VERSION 5.7 ;
BUSBITCHARS "[]" ;
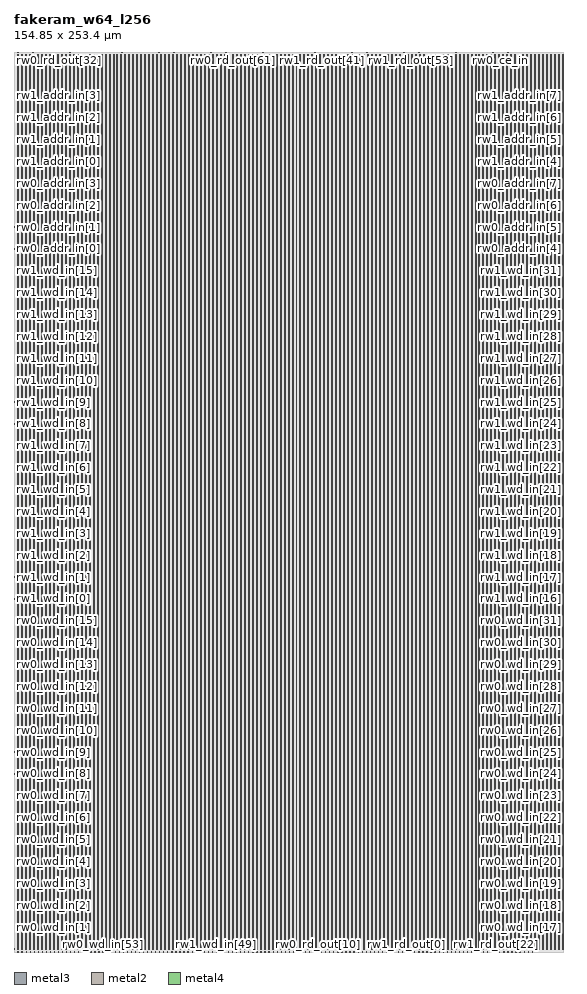
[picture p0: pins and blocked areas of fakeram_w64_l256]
MACRO fakeram_w64_l256
  FOREIGN fakeram_w64_l256 0 0 ;
  SYMMETRY X Y R90 ;
  SIZE 154.850 BY 253.400 ;
  CLASS BLOCK ;
  PIN rw0_wd_in[0]
    DIRECTION INPUT ;
    USE SIGNAL ;
    SHAPE ABUTMENT ;
    PORT
      LAYER metal3 ;
      RECT 0.000 0.805 0.210 0.875 ;
    END
  END rw0_wd_in[0]
  PIN rw0_wd_in[1]
    DIRECTION INPUT ;
    USE SIGNAL ;
    SHAPE ABUTMENT ;
    PORT
      LAYER metal3 ;
      RECT 0.000 6.965 0.210 7.035 ;
    END
  END rw0_wd_in[1]
  PIN rw0_wd_in[2]
    DIRECTION INPUT ;
    USE SIGNAL ;
    SHAPE ABUTMENT ;
    PORT
      LAYER metal3 ;
      RECT 0.000 13.125 0.210 13.195 ;
    END
  END rw0_wd_in[2]
  PIN rw0_wd_in[3]
    DIRECTION INPUT ;
    USE SIGNAL ;
    SHAPE ABUTMENT ;
    PORT
      LAYER metal3 ;
      RECT 0.000 19.285 0.210 19.355 ;
    END
  END rw0_wd_in[3]
  PIN rw0_wd_in[4]
    DIRECTION INPUT ;
    USE SIGNAL ;
    SHAPE ABUTMENT ;
    PORT
      LAYER metal3 ;
      RECT 0.000 25.445 0.210 25.515 ;
    END
  END rw0_wd_in[4]
  PIN rw0_wd_in[5]
    DIRECTION INPUT ;
    USE SIGNAL ;
    SHAPE ABUTMENT ;
    PORT
      LAYER metal3 ;
      RECT 0.000 31.605 0.210 31.675 ;
    END
  END rw0_wd_in[5]
  PIN rw0_wd_in[6]
    DIRECTION INPUT ;
    USE SIGNAL ;
    SHAPE ABUTMENT ;
    PORT
      LAYER metal3 ;
      RECT 0.000 37.765 0.210 37.835 ;
    END
  END rw0_wd_in[6]
  PIN rw0_wd_in[7]
    DIRECTION INPUT ;
    USE SIGNAL ;
    SHAPE ABUTMENT ;
    PORT
      LAYER metal3 ;
      RECT 0.000 43.925 0.210 43.995 ;
    END
  END rw0_wd_in[7]
  PIN rw0_wd_in[8]
    DIRECTION INPUT ;
    USE SIGNAL ;
    SHAPE ABUTMENT ;
    PORT
      LAYER metal3 ;
      RECT 0.000 50.085 0.210 50.155 ;
    END
  END rw0_wd_in[8]
  PIN rw0_wd_in[9]
    DIRECTION INPUT ;
    USE SIGNAL ;
    SHAPE ABUTMENT ;
    PORT
      LAYER metal3 ;
      RECT 0.000 56.245 0.210 56.315 ;
    END
  END rw0_wd_in[9]
  PIN rw0_wd_in[10]
    DIRECTION INPUT ;
    USE SIGNAL ;
    SHAPE ABUTMENT ;
    PORT
      LAYER metal3 ;
      RECT 0.000 62.405 0.210 62.475 ;
    END
  END rw0_wd_in[10]
  PIN rw0_wd_in[11]
    DIRECTION INPUT ;
    USE SIGNAL ;
    SHAPE ABUTMENT ;
    PORT
      LAYER metal3 ;
      RECT 0.000 68.565 0.210 68.635 ;
    END
  END rw0_wd_in[11]
  PIN rw0_wd_in[12]
    DIRECTION INPUT ;
    USE SIGNAL ;
    SHAPE ABUTMENT ;
    PORT
      LAYER metal3 ;
      RECT 0.000 74.725 0.210 74.795 ;
    END
  END rw0_wd_in[12]
  PIN rw0_wd_in[13]
    DIRECTION INPUT ;
    USE SIGNAL ;
    SHAPE ABUTMENT ;
    PORT
      LAYER metal3 ;
      RECT 0.000 80.885 0.210 80.955 ;
    END
  END rw0_wd_in[13]
  PIN rw0_wd_in[14]
    DIRECTION INPUT ;
    USE SIGNAL ;
    SHAPE ABUTMENT ;
    PORT
      LAYER metal3 ;
      RECT 0.000 87.045 0.210 87.115 ;
    END
  END rw0_wd_in[14]
  PIN rw0_wd_in[15]
    DIRECTION INPUT ;
    USE SIGNAL ;
    SHAPE ABUTMENT ;
    PORT
      LAYER metal3 ;
      RECT 0.000 93.205 0.210 93.275 ;
    END
  END rw0_wd_in[15]
  PIN rw0_wd_in[16]
    DIRECTION INPUT ;
    USE SIGNAL ;
    SHAPE ABUTMENT ;
    PORT
      LAYER metal3 ;
      RECT 154.640 0.805 154.850 0.875 ;
    END
  END rw0_wd_in[16]
  PIN rw0_wd_in[17]
    DIRECTION INPUT ;
    USE SIGNAL ;
    SHAPE ABUTMENT ;
    PORT
      LAYER metal3 ;
      RECT 154.640 6.965 154.850 7.035 ;
    END
  END rw0_wd_in[17]
  PIN rw0_wd_in[18]
    DIRECTION INPUT ;
    USE SIGNAL ;
    SHAPE ABUTMENT ;
    PORT
      LAYER metal3 ;
      RECT 154.640 13.125 154.850 13.195 ;
    END
  END rw0_wd_in[18]
  PIN rw0_wd_in[19]
    DIRECTION INPUT ;
    USE SIGNAL ;
    SHAPE ABUTMENT ;
    PORT
      LAYER metal3 ;
      RECT 154.640 19.285 154.850 19.355 ;
    END
  END rw0_wd_in[19]
  PIN rw0_wd_in[20]
    DIRECTION INPUT ;
    USE SIGNAL ;
    SHAPE ABUTMENT ;
    PORT
      LAYER metal3 ;
      RECT 154.640 25.445 154.850 25.515 ;
    END
  END rw0_wd_in[20]
  PIN rw0_wd_in[21]
    DIRECTION INPUT ;
    USE SIGNAL ;
    SHAPE ABUTMENT ;
    PORT
      LAYER metal3 ;
      RECT 154.640 31.605 154.850 31.675 ;
    END
  END rw0_wd_in[21]
  PIN rw0_wd_in[22]
    DIRECTION INPUT ;
    USE SIGNAL ;
    SHAPE ABUTMENT ;
    PORT
      LAYER metal3 ;
      RECT 154.640 37.765 154.850 37.835 ;
    END
  END rw0_wd_in[22]
  PIN rw0_wd_in[23]
    DIRECTION INPUT ;
    USE SIGNAL ;
    SHAPE ABUTMENT ;
    PORT
      LAYER metal3 ;
      RECT 154.640 43.925 154.850 43.995 ;
    END
  END rw0_wd_in[23]
  PIN rw0_wd_in[24]
    DIRECTION INPUT ;
    USE SIGNAL ;
    SHAPE ABUTMENT ;
    PORT
      LAYER metal3 ;
      RECT 154.640 50.085 154.850 50.155 ;
    END
  END rw0_wd_in[24]
  PIN rw0_wd_in[25]
    DIRECTION INPUT ;
    USE SIGNAL ;
    SHAPE ABUTMENT ;
    PORT
      LAYER metal3 ;
      RECT 154.640 56.245 154.850 56.315 ;
    END
  END rw0_wd_in[25]
  PIN rw0_wd_in[26]
    DIRECTION INPUT ;
    USE SIGNAL ;
    SHAPE ABUTMENT ;
    PORT
      LAYER metal3 ;
      RECT 154.640 62.405 154.850 62.475 ;
    END
  END rw0_wd_in[26]
  PIN rw0_wd_in[27]
    DIRECTION INPUT ;
    USE SIGNAL ;
    SHAPE ABUTMENT ;
    PORT
      LAYER metal3 ;
      RECT 154.640 68.565 154.850 68.635 ;
    END
  END rw0_wd_in[27]
  PIN rw0_wd_in[28]
    DIRECTION INPUT ;
    USE SIGNAL ;
    SHAPE ABUTMENT ;
    PORT
      LAYER metal3 ;
      RECT 154.640 74.725 154.850 74.795 ;
    END
  END rw0_wd_in[28]
  PIN rw0_wd_in[29]
    DIRECTION INPUT ;
    USE SIGNAL ;
    SHAPE ABUTMENT ;
    PORT
      LAYER metal3 ;
      RECT 154.640 80.885 154.850 80.955 ;
    END
  END rw0_wd_in[29]
  PIN rw0_wd_in[30]
    DIRECTION INPUT ;
    USE SIGNAL ;
    SHAPE ABUTMENT ;
    PORT
      LAYER metal3 ;
      RECT 154.640 87.045 154.850 87.115 ;
    END
  END rw0_wd_in[30]
  PIN rw0_wd_in[31]
    DIRECTION INPUT ;
    USE SIGNAL ;
    SHAPE ABUTMENT ;
    PORT
      LAYER metal3 ;
      RECT 154.640 93.205 154.850 93.275 ;
    END
  END rw0_wd_in[31]
  PIN rw0_wd_in[32]
    DIRECTION INPUT ;
    USE SIGNAL ;
    SHAPE ABUTMENT ;
    PORT
      LAYER metal2 ;
      RECT 1.105 0.000 1.175 0.210 ;
    END
  END rw0_wd_in[32]
  PIN rw0_wd_in[33]
    DIRECTION INPUT ;
    USE SIGNAL ;
    SHAPE ABUTMENT ;
    PORT
      LAYER metal2 ;
      RECT 2.245 0.000 2.315 0.210 ;
    END
  END rw0_wd_in[33]
  PIN rw0_wd_in[34]
    DIRECTION INPUT ;
    USE SIGNAL ;
    SHAPE ABUTMENT ;
    PORT
      LAYER metal2 ;
      RECT 3.385 0.000 3.455 0.210 ;
    END
  END rw0_wd_in[34]
  PIN rw0_wd_in[35]
    DIRECTION INPUT ;
    USE SIGNAL ;
    SHAPE ABUTMENT ;
    PORT
      LAYER metal2 ;
      RECT 4.525 0.000 4.595 0.210 ;
    END
  END rw0_wd_in[35]
  PIN rw0_wd_in[36]
    DIRECTION INPUT ;
    USE SIGNAL ;
    SHAPE ABUTMENT ;
    PORT
      LAYER metal2 ;
      RECT 5.665 0.000 5.735 0.210 ;
    END
  END rw0_wd_in[36]
  PIN rw0_wd_in[37]
    DIRECTION INPUT ;
    USE SIGNAL ;
    SHAPE ABUTMENT ;
    PORT
      LAYER metal2 ;
      RECT 6.805 0.000 6.875 0.210 ;
    END
  END rw0_wd_in[37]
  PIN rw0_wd_in[38]
    DIRECTION INPUT ;
    USE SIGNAL ;
    SHAPE ABUTMENT ;
    PORT
      LAYER metal2 ;
      RECT 7.945 0.000 8.015 0.210 ;
    END
  END rw0_wd_in[38]
  PIN rw0_wd_in[39]
    DIRECTION INPUT ;
    USE SIGNAL ;
    SHAPE ABUTMENT ;
    PORT
      LAYER metal2 ;
      RECT 9.085 0.000 9.155 0.210 ;
    END
  END rw0_wd_in[39]
  PIN rw0_wd_in[40]
    DIRECTION INPUT ;
    USE SIGNAL ;
    SHAPE ABUTMENT ;
    PORT
      LAYER metal2 ;
      RECT 10.225 0.000 10.295 0.210 ;
    END
  END rw0_wd_in[40]
  PIN rw0_wd_in[41]
    DIRECTION INPUT ;
    USE SIGNAL ;
    SHAPE ABUTMENT ;
    PORT
      LAYER metal2 ;
      RECT 11.365 0.000 11.435 0.210 ;
    END
  END rw0_wd_in[41]
  PIN rw0_wd_in[42]
    DIRECTION INPUT ;
    USE SIGNAL ;
    SHAPE ABUTMENT ;
    PORT
      LAYER metal2 ;
      RECT 12.505 0.000 12.575 0.210 ;
    END
  END rw0_wd_in[42]
  PIN rw0_wd_in[43]
    DIRECTION INPUT ;
    USE SIGNAL ;
    SHAPE ABUTMENT ;
    PORT
      LAYER metal2 ;
      RECT 13.645 0.000 13.715 0.210 ;
    END
  END rw0_wd_in[43]
  PIN rw0_wd_in[44]
    DIRECTION INPUT ;
    USE SIGNAL ;
    SHAPE ABUTMENT ;
    PORT
      LAYER metal2 ;
      RECT 14.785 0.000 14.855 0.210 ;
    END
  END rw0_wd_in[44]
  PIN rw0_wd_in[45]
    DIRECTION INPUT ;
    USE SIGNAL ;
    SHAPE ABUTMENT ;
    PORT
      LAYER metal2 ;
      RECT 15.925 0.000 15.995 0.210 ;
    END
  END rw0_wd_in[45]
  PIN rw0_wd_in[46]
    DIRECTION INPUT ;
    USE SIGNAL ;
    SHAPE ABUTMENT ;
    PORT
      LAYER metal2 ;
      RECT 17.065 0.000 17.135 0.210 ;
    END
  END rw0_wd_in[46]
  PIN rw0_wd_in[47]
    DIRECTION INPUT ;
    USE SIGNAL ;
    SHAPE ABUTMENT ;
    PORT
      LAYER metal2 ;
      RECT 18.205 0.000 18.275 0.210 ;
    END
  END rw0_wd_in[47]
  PIN rw0_wd_in[48]
    DIRECTION INPUT ;
    USE SIGNAL ;
    SHAPE ABUTMENT ;
    PORT
      LAYER metal2 ;
      RECT 19.345 0.000 19.415 0.210 ;
    END
  END rw0_wd_in[48]
  PIN rw0_wd_in[49]
    DIRECTION INPUT ;
    USE SIGNAL ;
    SHAPE ABUTMENT ;
    PORT
      LAYER metal2 ;
      RECT 20.485 0.000 20.555 0.210 ;
    END
  END rw0_wd_in[49]
  PIN rw0_wd_in[50]
    DIRECTION INPUT ;
    USE SIGNAL ;
    SHAPE ABUTMENT ;
    PORT
      LAYER metal2 ;
      RECT 21.625 0.000 21.695 0.210 ;
    END
  END rw0_wd_in[50]
  PIN rw0_wd_in[51]
    DIRECTION INPUT ;
    USE SIGNAL ;
    SHAPE ABUTMENT ;
    PORT
      LAYER metal2 ;
      RECT 22.765 0.000 22.835 0.210 ;
    END
  END rw0_wd_in[51]
  PIN rw0_wd_in[52]
    DIRECTION INPUT ;
    USE SIGNAL ;
    SHAPE ABUTMENT ;
    PORT
      LAYER metal2 ;
      RECT 23.905 0.000 23.975 0.210 ;
    END
  END rw0_wd_in[52]
  PIN rw0_wd_in[53]
    DIRECTION INPUT ;
    USE SIGNAL ;
    SHAPE ABUTMENT ;
    PORT
      LAYER metal2 ;
      RECT 25.045 0.000 25.115 0.210 ;
    END
  END rw0_wd_in[53]
  PIN rw0_wd_in[54]
    DIRECTION INPUT ;
    USE SIGNAL ;
    SHAPE ABUTMENT ;
    PORT
      LAYER metal2 ;
      RECT 26.185 0.000 26.255 0.210 ;
    END
  END rw0_wd_in[54]
  PIN rw0_wd_in[55]
    DIRECTION INPUT ;
    USE SIGNAL ;
    SHAPE ABUTMENT ;
    PORT
      LAYER metal2 ;
      RECT 27.325 0.000 27.395 0.210 ;
    END
  END rw0_wd_in[55]
  PIN rw0_wd_in[56]
    DIRECTION INPUT ;
    USE SIGNAL ;
    SHAPE ABUTMENT ;
    PORT
      LAYER metal2 ;
      RECT 28.465 0.000 28.535 0.210 ;
    END
  END rw0_wd_in[56]
  PIN rw0_wd_in[57]
    DIRECTION INPUT ;
    USE SIGNAL ;
    SHAPE ABUTMENT ;
    PORT
      LAYER metal2 ;
      RECT 29.605 0.000 29.675 0.210 ;
    END
  END rw0_wd_in[57]
  PIN rw0_wd_in[58]
    DIRECTION INPUT ;
    USE SIGNAL ;
    SHAPE ABUTMENT ;
    PORT
      LAYER metal2 ;
      RECT 30.745 0.000 30.815 0.210 ;
    END
  END rw0_wd_in[58]
  PIN rw0_wd_in[59]
    DIRECTION INPUT ;
    USE SIGNAL ;
    SHAPE ABUTMENT ;
    PORT
      LAYER metal2 ;
      RECT 31.885 0.000 31.955 0.210 ;
    END
  END rw0_wd_in[59]
  PIN rw0_wd_in[60]
    DIRECTION INPUT ;
    USE SIGNAL ;
    SHAPE ABUTMENT ;
    PORT
      LAYER metal2 ;
      RECT 33.025 0.000 33.095 0.210 ;
    END
  END rw0_wd_in[60]
  PIN rw0_wd_in[61]
    DIRECTION INPUT ;
    USE SIGNAL ;
    SHAPE ABUTMENT ;
    PORT
      LAYER metal2 ;
      RECT 34.165 0.000 34.235 0.210 ;
    END
  END rw0_wd_in[61]
  PIN rw0_wd_in[62]
    DIRECTION INPUT ;
    USE SIGNAL ;
    SHAPE ABUTMENT ;
    PORT
      LAYER metal2 ;
      RECT 35.305 0.000 35.375 0.210 ;
    END
  END rw0_wd_in[62]
  PIN rw0_wd_in[63]
    DIRECTION INPUT ;
    USE SIGNAL ;
    SHAPE ABUTMENT ;
    PORT
      LAYER metal2 ;
      RECT 36.445 0.000 36.515 0.210 ;
    END
  END rw0_wd_in[63]
  PIN rw1_wd_in[0]
    DIRECTION INPUT ;
    USE SIGNAL ;
    SHAPE ABUTMENT ;
    PORT
      LAYER metal3 ;
      RECT 0.000 99.365 0.210 99.435 ;
    END
  END rw1_wd_in[0]
  PIN rw1_wd_in[1]
    DIRECTION INPUT ;
    USE SIGNAL ;
    SHAPE ABUTMENT ;
    PORT
      LAYER metal3 ;
      RECT 0.000 105.525 0.210 105.595 ;
    END
  END rw1_wd_in[1]
  PIN rw1_wd_in[2]
    DIRECTION INPUT ;
    USE SIGNAL ;
    SHAPE ABUTMENT ;
    PORT
      LAYER metal3 ;
      RECT 0.000 111.685 0.210 111.755 ;
    END
  END rw1_wd_in[2]
  PIN rw1_wd_in[3]
    DIRECTION INPUT ;
    USE SIGNAL ;
    SHAPE ABUTMENT ;
    PORT
      LAYER metal3 ;
      RECT 0.000 117.845 0.210 117.915 ;
    END
  END rw1_wd_in[3]
  PIN rw1_wd_in[4]
    DIRECTION INPUT ;
    USE SIGNAL ;
    SHAPE ABUTMENT ;
    PORT
      LAYER metal3 ;
      RECT 0.000 124.005 0.210 124.075 ;
    END
  END rw1_wd_in[4]
  PIN rw1_wd_in[5]
    DIRECTION INPUT ;
    USE SIGNAL ;
    SHAPE ABUTMENT ;
    PORT
      LAYER metal3 ;
      RECT 0.000 130.165 0.210 130.235 ;
    END
  END rw1_wd_in[5]
  PIN rw1_wd_in[6]
    DIRECTION INPUT ;
    USE SIGNAL ;
    SHAPE ABUTMENT ;
    PORT
      LAYER metal3 ;
      RECT 0.000 136.325 0.210 136.395 ;
    END
  END rw1_wd_in[6]
  PIN rw1_wd_in[7]
    DIRECTION INPUT ;
    USE SIGNAL ;
    SHAPE ABUTMENT ;
    PORT
      LAYER metal3 ;
      RECT 0.000 142.485 0.210 142.555 ;
    END
  END rw1_wd_in[7]
  PIN rw1_wd_in[8]
    DIRECTION INPUT ;
    USE SIGNAL ;
    SHAPE ABUTMENT ;
    PORT
      LAYER metal3 ;
      RECT 0.000 148.645 0.210 148.715 ;
    END
  END rw1_wd_in[8]
  PIN rw1_wd_in[9]
    DIRECTION INPUT ;
    USE SIGNAL ;
    SHAPE ABUTMENT ;
    PORT
      LAYER metal3 ;
      RECT 0.000 154.805 0.210 154.875 ;
    END
  END rw1_wd_in[9]
  PIN rw1_wd_in[10]
    DIRECTION INPUT ;
    USE SIGNAL ;
    SHAPE ABUTMENT ;
    PORT
      LAYER metal3 ;
      RECT 0.000 160.965 0.210 161.035 ;
    END
  END rw1_wd_in[10]
  PIN rw1_wd_in[11]
    DIRECTION INPUT ;
    USE SIGNAL ;
    SHAPE ABUTMENT ;
    PORT
      LAYER metal3 ;
      RECT 0.000 167.125 0.210 167.195 ;
    END
  END rw1_wd_in[11]
  PIN rw1_wd_in[12]
    DIRECTION INPUT ;
    USE SIGNAL ;
    SHAPE ABUTMENT ;
    PORT
      LAYER metal3 ;
      RECT 0.000 173.285 0.210 173.355 ;
    END
  END rw1_wd_in[12]
  PIN rw1_wd_in[13]
    DIRECTION INPUT ;
    USE SIGNAL ;
    SHAPE ABUTMENT ;
    PORT
      LAYER metal3 ;
      RECT 0.000 179.445 0.210 179.515 ;
    END
  END rw1_wd_in[13]
  PIN rw1_wd_in[14]
    DIRECTION INPUT ;
    USE SIGNAL ;
    SHAPE ABUTMENT ;
    PORT
      LAYER metal3 ;
      RECT 0.000 185.605 0.210 185.675 ;
    END
  END rw1_wd_in[14]
  PIN rw1_wd_in[15]
    DIRECTION INPUT ;
    USE SIGNAL ;
    SHAPE ABUTMENT ;
    PORT
      LAYER metal3 ;
      RECT 0.000 191.765 0.210 191.835 ;
    END
  END rw1_wd_in[15]
  PIN rw1_wd_in[16]
    DIRECTION INPUT ;
    USE SIGNAL ;
    SHAPE ABUTMENT ;
    PORT
      LAYER metal3 ;
      RECT 154.640 99.365 154.850 99.435 ;
    END
  END rw1_wd_in[16]
  PIN rw1_wd_in[17]
    DIRECTION INPUT ;
    USE SIGNAL ;
    SHAPE ABUTMENT ;
    PORT
      LAYER metal3 ;
      RECT 154.640 105.525 154.850 105.595 ;
    END
  END rw1_wd_in[17]
  PIN rw1_wd_in[18]
    DIRECTION INPUT ;
    USE SIGNAL ;
    SHAPE ABUTMENT ;
    PORT
      LAYER metal3 ;
      RECT 154.640 111.685 154.850 111.755 ;
    END
  END rw1_wd_in[18]
  PIN rw1_wd_in[19]
    DIRECTION INPUT ;
    USE SIGNAL ;
    SHAPE ABUTMENT ;
    PORT
      LAYER metal3 ;
      RECT 154.640 117.845 154.850 117.915 ;
    END
  END rw1_wd_in[19]
  PIN rw1_wd_in[20]
    DIRECTION INPUT ;
    USE SIGNAL ;
    SHAPE ABUTMENT ;
    PORT
      LAYER metal3 ;
      RECT 154.640 124.005 154.850 124.075 ;
    END
  END rw1_wd_in[20]
  PIN rw1_wd_in[21]
    DIRECTION INPUT ;
    USE SIGNAL ;
    SHAPE ABUTMENT ;
    PORT
      LAYER metal3 ;
      RECT 154.640 130.165 154.850 130.235 ;
    END
  END rw1_wd_in[21]
  PIN rw1_wd_in[22]
    DIRECTION INPUT ;
    USE SIGNAL ;
    SHAPE ABUTMENT ;
    PORT
      LAYER metal3 ;
      RECT 154.640 136.325 154.850 136.395 ;
    END
  END rw1_wd_in[22]
  PIN rw1_wd_in[23]
    DIRECTION INPUT ;
    USE SIGNAL ;
    SHAPE ABUTMENT ;
    PORT
      LAYER metal3 ;
      RECT 154.640 142.485 154.850 142.555 ;
    END
  END rw1_wd_in[23]
  PIN rw1_wd_in[24]
    DIRECTION INPUT ;
    USE SIGNAL ;
    SHAPE ABUTMENT ;
    PORT
      LAYER metal3 ;
      RECT 154.640 148.645 154.850 148.715 ;
    END
  END rw1_wd_in[24]
  PIN rw1_wd_in[25]
    DIRECTION INPUT ;
    USE SIGNAL ;
    SHAPE ABUTMENT ;
    PORT
      LAYER metal3 ;
      RECT 154.640 154.805 154.850 154.875 ;
    END
  END rw1_wd_in[25]
  PIN rw1_wd_in[26]
    DIRECTION INPUT ;
    USE SIGNAL ;
    SHAPE ABUTMENT ;
    PORT
      LAYER metal3 ;
      RECT 154.640 160.965 154.850 161.035 ;
    END
  END rw1_wd_in[26]
  PIN rw1_wd_in[27]
    DIRECTION INPUT ;
    USE SIGNAL ;
    SHAPE ABUTMENT ;
    PORT
      LAYER metal3 ;
      RECT 154.640 167.125 154.850 167.195 ;
    END
  END rw1_wd_in[27]
  PIN rw1_wd_in[28]
    DIRECTION INPUT ;
    USE SIGNAL ;
    SHAPE ABUTMENT ;
    PORT
      LAYER metal3 ;
      RECT 154.640 173.285 154.850 173.355 ;
    END
  END rw1_wd_in[28]
  PIN rw1_wd_in[29]
    DIRECTION INPUT ;
    USE SIGNAL ;
    SHAPE ABUTMENT ;
    PORT
      LAYER metal3 ;
      RECT 154.640 179.445 154.850 179.515 ;
    END
  END rw1_wd_in[29]
  PIN rw1_wd_in[30]
    DIRECTION INPUT ;
    USE SIGNAL ;
    SHAPE ABUTMENT ;
    PORT
      LAYER metal3 ;
      RECT 154.640 185.605 154.850 185.675 ;
    END
  END rw1_wd_in[30]
  PIN rw1_wd_in[31]
    DIRECTION INPUT ;
    USE SIGNAL ;
    SHAPE ABUTMENT ;
    PORT
      LAYER metal3 ;
      RECT 154.640 191.765 154.850 191.835 ;
    END
  END rw1_wd_in[31]
  PIN rw1_wd_in[32]
    DIRECTION INPUT ;
    USE SIGNAL ;
    SHAPE ABUTMENT ;
    PORT
      LAYER metal2 ;
      RECT 37.585 0.000 37.655 0.210 ;
    END
  END rw1_wd_in[32]
  PIN rw1_wd_in[33]
    DIRECTION INPUT ;
    USE SIGNAL ;
    SHAPE ABUTMENT ;
    PORT
      LAYER metal2 ;
      RECT 38.725 0.000 38.795 0.210 ;
    END
  END rw1_wd_in[33]
  PIN rw1_wd_in[34]
    DIRECTION INPUT ;
    USE SIGNAL ;
    SHAPE ABUTMENT ;
    PORT
      LAYER metal2 ;
      RECT 39.865 0.000 39.935 0.210 ;
    END
  END rw1_wd_in[34]
  PIN rw1_wd_in[35]
    DIRECTION INPUT ;
    USE SIGNAL ;
    SHAPE ABUTMENT ;
    PORT
      LAYER metal2 ;
      RECT 41.005 0.000 41.075 0.210 ;
    END
  END rw1_wd_in[35]
  PIN rw1_wd_in[36]
    DIRECTION INPUT ;
    USE SIGNAL ;
    SHAPE ABUTMENT ;
    PORT
      LAYER metal2 ;
      RECT 42.145 0.000 42.215 0.210 ;
    END
  END rw1_wd_in[36]
  PIN rw1_wd_in[37]
    DIRECTION INPUT ;
    USE SIGNAL ;
    SHAPE ABUTMENT ;
    PORT
      LAYER metal2 ;
      RECT 43.285 0.000 43.355 0.210 ;
    END
  END rw1_wd_in[37]
  PIN rw1_wd_in[38]
    DIRECTION INPUT ;
    USE SIGNAL ;
    SHAPE ABUTMENT ;
    PORT
      LAYER metal2 ;
      RECT 44.425 0.000 44.495 0.210 ;
    END
  END rw1_wd_in[38]
  PIN rw1_wd_in[39]
    DIRECTION INPUT ;
    USE SIGNAL ;
    SHAPE ABUTMENT ;
    PORT
      LAYER metal2 ;
      RECT 45.565 0.000 45.635 0.210 ;
    END
  END rw1_wd_in[39]
  PIN rw1_wd_in[40]
    DIRECTION INPUT ;
    USE SIGNAL ;
    SHAPE ABUTMENT ;
    PORT
      LAYER metal2 ;
      RECT 46.705 0.000 46.775 0.210 ;
    END
  END rw1_wd_in[40]
  PIN rw1_wd_in[41]
    DIRECTION INPUT ;
    USE SIGNAL ;
    SHAPE ABUTMENT ;
    PORT
      LAYER metal2 ;
      RECT 47.845 0.000 47.915 0.210 ;
    END
  END rw1_wd_in[41]
  PIN rw1_wd_in[42]
    DIRECTION INPUT ;
    USE SIGNAL ;
    SHAPE ABUTMENT ;
    PORT
      LAYER metal2 ;
      RECT 48.985 0.000 49.055 0.210 ;
    END
  END rw1_wd_in[42]
  PIN rw1_wd_in[43]
    DIRECTION INPUT ;
    USE SIGNAL ;
    SHAPE ABUTMENT ;
    PORT
      LAYER metal2 ;
      RECT 50.125 0.000 50.195 0.210 ;
    END
  END rw1_wd_in[43]
  PIN rw1_wd_in[44]
    DIRECTION INPUT ;
    USE SIGNAL ;
    SHAPE ABUTMENT ;
    PORT
      LAYER metal2 ;
      RECT 51.265 0.000 51.335 0.210 ;
    END
  END rw1_wd_in[44]
  PIN rw1_wd_in[45]
    DIRECTION INPUT ;
    USE SIGNAL ;
    SHAPE ABUTMENT ;
    PORT
      LAYER metal2 ;
      RECT 52.405 0.000 52.475 0.210 ;
    END
  END rw1_wd_in[45]
  PIN rw1_wd_in[46]
    DIRECTION INPUT ;
    USE SIGNAL ;
    SHAPE ABUTMENT ;
    PORT
      LAYER metal2 ;
      RECT 53.545 0.000 53.615 0.210 ;
    END
  END rw1_wd_in[46]
  PIN rw1_wd_in[47]
    DIRECTION INPUT ;
    USE SIGNAL ;
    SHAPE ABUTMENT ;
    PORT
      LAYER metal2 ;
      RECT 54.685 0.000 54.755 0.210 ;
    END
  END rw1_wd_in[47]
  PIN rw1_wd_in[48]
    DIRECTION INPUT ;
    USE SIGNAL ;
    SHAPE ABUTMENT ;
    PORT
      LAYER metal2 ;
      RECT 55.825 0.000 55.895 0.210 ;
    END
  END rw1_wd_in[48]
  PIN rw1_wd_in[49]
    DIRECTION INPUT ;
    USE SIGNAL ;
    SHAPE ABUTMENT ;
    PORT
      LAYER metal2 ;
      RECT 56.965 0.000 57.035 0.210 ;
    END
  END rw1_wd_in[49]
  PIN rw1_wd_in[50]
    DIRECTION INPUT ;
    USE SIGNAL ;
    SHAPE ABUTMENT ;
    PORT
      LAYER metal2 ;
      RECT 58.105 0.000 58.175 0.210 ;
    END
  END rw1_wd_in[50]
  PIN rw1_wd_in[51]
    DIRECTION INPUT ;
    USE SIGNAL ;
    SHAPE ABUTMENT ;
    PORT
      LAYER metal2 ;
      RECT 59.245 0.000 59.315 0.210 ;
    END
  END rw1_wd_in[51]
  PIN rw1_wd_in[52]
    DIRECTION INPUT ;
    USE SIGNAL ;
    SHAPE ABUTMENT ;
    PORT
      LAYER metal2 ;
      RECT 60.385 0.000 60.455 0.210 ;
    END
  END rw1_wd_in[52]
  PIN rw1_wd_in[53]
    DIRECTION INPUT ;
    USE SIGNAL ;
    SHAPE ABUTMENT ;
    PORT
      LAYER metal2 ;
      RECT 61.525 0.000 61.595 0.210 ;
    END
  END rw1_wd_in[53]
  PIN rw1_wd_in[54]
    DIRECTION INPUT ;
    USE SIGNAL ;
    SHAPE ABUTMENT ;
    PORT
      LAYER metal2 ;
      RECT 62.665 0.000 62.735 0.210 ;
    END
  END rw1_wd_in[54]
  PIN rw1_wd_in[55]
    DIRECTION INPUT ;
    USE SIGNAL ;
    SHAPE ABUTMENT ;
    PORT
      LAYER metal2 ;
      RECT 63.805 0.000 63.875 0.210 ;
    END
  END rw1_wd_in[55]
  PIN rw1_wd_in[56]
    DIRECTION INPUT ;
    USE SIGNAL ;
    SHAPE ABUTMENT ;
    PORT
      LAYER metal2 ;
      RECT 64.945 0.000 65.015 0.210 ;
    END
  END rw1_wd_in[56]
  PIN rw1_wd_in[57]
    DIRECTION INPUT ;
    USE SIGNAL ;
    SHAPE ABUTMENT ;
    PORT
      LAYER metal2 ;
      RECT 66.085 0.000 66.155 0.210 ;
    END
  END rw1_wd_in[57]
  PIN rw1_wd_in[58]
    DIRECTION INPUT ;
    USE SIGNAL ;
    SHAPE ABUTMENT ;
    PORT
      LAYER metal2 ;
      RECT 67.225 0.000 67.295 0.210 ;
    END
  END rw1_wd_in[58]
  PIN rw1_wd_in[59]
    DIRECTION INPUT ;
    USE SIGNAL ;
    SHAPE ABUTMENT ;
    PORT
      LAYER metal2 ;
      RECT 68.365 0.000 68.435 0.210 ;
    END
  END rw1_wd_in[59]
  PIN rw1_wd_in[60]
    DIRECTION INPUT ;
    USE SIGNAL ;
    SHAPE ABUTMENT ;
    PORT
      LAYER metal2 ;
      RECT 69.505 0.000 69.575 0.210 ;
    END
  END rw1_wd_in[60]
  PIN rw1_wd_in[61]
    DIRECTION INPUT ;
    USE SIGNAL ;
    SHAPE ABUTMENT ;
    PORT
      LAYER metal2 ;
      RECT 70.645 0.000 70.715 0.210 ;
    END
  END rw1_wd_in[61]
  PIN rw1_wd_in[62]
    DIRECTION INPUT ;
    USE SIGNAL ;
    SHAPE ABUTMENT ;
    PORT
      LAYER metal2 ;
      RECT 71.785 0.000 71.855 0.210 ;
    END
  END rw1_wd_in[62]
  PIN rw1_wd_in[63]
    DIRECTION INPUT ;
    USE SIGNAL ;
    SHAPE ABUTMENT ;
    PORT
      LAYER metal2 ;
      RECT 72.925 0.000 72.995 0.210 ;
    END
  END rw1_wd_in[63]
  PIN rw0_rd_out[0]
    DIRECTION OUTPUT ;
    USE SIGNAL ;
    SHAPE ABUTMENT ;
    PORT
      LAYER metal2 ;
      RECT 74.065 0.000 74.135 0.210 ;
    END
  END rw0_rd_out[0]
  PIN rw0_rd_out[1]
    DIRECTION OUTPUT ;
    USE SIGNAL ;
    SHAPE ABUTMENT ;
    PORT
      LAYER metal2 ;
      RECT 75.205 0.000 75.275 0.210 ;
    END
  END rw0_rd_out[1]
  PIN rw0_rd_out[2]
    DIRECTION OUTPUT ;
    USE SIGNAL ;
    SHAPE ABUTMENT ;
    PORT
      LAYER metal2 ;
      RECT 76.345 0.000 76.415 0.210 ;
    END
  END rw0_rd_out[2]
  PIN rw0_rd_out[3]
    DIRECTION OUTPUT ;
    USE SIGNAL ;
    SHAPE ABUTMENT ;
    PORT
      LAYER metal2 ;
      RECT 77.485 0.000 77.555 0.210 ;
    END
  END rw0_rd_out[3]
  PIN rw0_rd_out[4]
    DIRECTION OUTPUT ;
    USE SIGNAL ;
    SHAPE ABUTMENT ;
    PORT
      LAYER metal2 ;
      RECT 78.625 0.000 78.695 0.210 ;
    END
  END rw0_rd_out[4]
  PIN rw0_rd_out[5]
    DIRECTION OUTPUT ;
    USE SIGNAL ;
    SHAPE ABUTMENT ;
    PORT
      LAYER metal2 ;
      RECT 79.765 0.000 79.835 0.210 ;
    END
  END rw0_rd_out[5]
  PIN rw0_rd_out[6]
    DIRECTION OUTPUT ;
    USE SIGNAL ;
    SHAPE ABUTMENT ;
    PORT
      LAYER metal2 ;
      RECT 80.905 0.000 80.975 0.210 ;
    END
  END rw0_rd_out[6]
  PIN rw0_rd_out[7]
    DIRECTION OUTPUT ;
    USE SIGNAL ;
    SHAPE ABUTMENT ;
    PORT
      LAYER metal2 ;
      RECT 82.045 0.000 82.115 0.210 ;
    END
  END rw0_rd_out[7]
  PIN rw0_rd_out[8]
    DIRECTION OUTPUT ;
    USE SIGNAL ;
    SHAPE ABUTMENT ;
    PORT
      LAYER metal2 ;
      RECT 83.185 0.000 83.255 0.210 ;
    END
  END rw0_rd_out[8]
  PIN rw0_rd_out[9]
    DIRECTION OUTPUT ;
    USE SIGNAL ;
    SHAPE ABUTMENT ;
    PORT
      LAYER metal2 ;
      RECT 84.325 0.000 84.395 0.210 ;
    END
  END rw0_rd_out[9]
  PIN rw0_rd_out[10]
    DIRECTION OUTPUT ;
    USE SIGNAL ;
    SHAPE ABUTMENT ;
    PORT
      LAYER metal2 ;
      RECT 85.465 0.000 85.535 0.210 ;
    END
  END rw0_rd_out[10]
  PIN rw0_rd_out[11]
    DIRECTION OUTPUT ;
    USE SIGNAL ;
    SHAPE ABUTMENT ;
    PORT
      LAYER metal2 ;
      RECT 86.605 0.000 86.675 0.210 ;
    END
  END rw0_rd_out[11]
  PIN rw0_rd_out[12]
    DIRECTION OUTPUT ;
    USE SIGNAL ;
    SHAPE ABUTMENT ;
    PORT
      LAYER metal2 ;
      RECT 87.745 0.000 87.815 0.210 ;
    END
  END rw0_rd_out[12]
  PIN rw0_rd_out[13]
    DIRECTION OUTPUT ;
    USE SIGNAL ;
    SHAPE ABUTMENT ;
    PORT
      LAYER metal2 ;
      RECT 88.885 0.000 88.955 0.210 ;
    END
  END rw0_rd_out[13]
  PIN rw0_rd_out[14]
    DIRECTION OUTPUT ;
    USE SIGNAL ;
    SHAPE ABUTMENT ;
    PORT
      LAYER metal2 ;
      RECT 90.025 0.000 90.095 0.210 ;
    END
  END rw0_rd_out[14]
  PIN rw0_rd_out[15]
    DIRECTION OUTPUT ;
    USE SIGNAL ;
    SHAPE ABUTMENT ;
    PORT
      LAYER metal2 ;
      RECT 91.165 0.000 91.235 0.210 ;
    END
  END rw0_rd_out[15]
  PIN rw0_rd_out[16]
    DIRECTION OUTPUT ;
    USE SIGNAL ;
    SHAPE ABUTMENT ;
    PORT
      LAYER metal2 ;
      RECT 92.305 0.000 92.375 0.210 ;
    END
  END rw0_rd_out[16]
  PIN rw0_rd_out[17]
    DIRECTION OUTPUT ;
    USE SIGNAL ;
    SHAPE ABUTMENT ;
    PORT
      LAYER metal2 ;
      RECT 93.445 0.000 93.515 0.210 ;
    END
  END rw0_rd_out[17]
  PIN rw0_rd_out[18]
    DIRECTION OUTPUT ;
    USE SIGNAL ;
    SHAPE ABUTMENT ;
    PORT
      LAYER metal2 ;
      RECT 94.585 0.000 94.655 0.210 ;
    END
  END rw0_rd_out[18]
  PIN rw0_rd_out[19]
    DIRECTION OUTPUT ;
    USE SIGNAL ;
    SHAPE ABUTMENT ;
    PORT
      LAYER metal2 ;
      RECT 95.725 0.000 95.795 0.210 ;
    END
  END rw0_rd_out[19]
  PIN rw0_rd_out[20]
    DIRECTION OUTPUT ;
    USE SIGNAL ;
    SHAPE ABUTMENT ;
    PORT
      LAYER metal2 ;
      RECT 96.865 0.000 96.935 0.210 ;
    END
  END rw0_rd_out[20]
  PIN rw0_rd_out[21]
    DIRECTION OUTPUT ;
    USE SIGNAL ;
    SHAPE ABUTMENT ;
    PORT
      LAYER metal2 ;
      RECT 98.005 0.000 98.075 0.210 ;
    END
  END rw0_rd_out[21]
  PIN rw0_rd_out[22]
    DIRECTION OUTPUT ;
    USE SIGNAL ;
    SHAPE ABUTMENT ;
    PORT
      LAYER metal2 ;
      RECT 99.145 0.000 99.215 0.210 ;
    END
  END rw0_rd_out[22]
  PIN rw0_rd_out[23]
    DIRECTION OUTPUT ;
    USE SIGNAL ;
    SHAPE ABUTMENT ;
    PORT
      LAYER metal2 ;
      RECT 100.285 0.000 100.355 0.210 ;
    END
  END rw0_rd_out[23]
  PIN rw0_rd_out[24]
    DIRECTION OUTPUT ;
    USE SIGNAL ;
    SHAPE ABUTMENT ;
    PORT
      LAYER metal2 ;
      RECT 101.425 0.000 101.495 0.210 ;
    END
  END rw0_rd_out[24]
  PIN rw0_rd_out[25]
    DIRECTION OUTPUT ;
    USE SIGNAL ;
    SHAPE ABUTMENT ;
    PORT
      LAYER metal2 ;
      RECT 102.565 0.000 102.635 0.210 ;
    END
  END rw0_rd_out[25]
  PIN rw0_rd_out[26]
    DIRECTION OUTPUT ;
    USE SIGNAL ;
    SHAPE ABUTMENT ;
    PORT
      LAYER metal2 ;
      RECT 103.705 0.000 103.775 0.210 ;
    END
  END rw0_rd_out[26]
  PIN rw0_rd_out[27]
    DIRECTION OUTPUT ;
    USE SIGNAL ;
    SHAPE ABUTMENT ;
    PORT
      LAYER metal2 ;
      RECT 104.845 0.000 104.915 0.210 ;
    END
  END rw0_rd_out[27]
  PIN rw0_rd_out[28]
    DIRECTION OUTPUT ;
    USE SIGNAL ;
    SHAPE ABUTMENT ;
    PORT
      LAYER metal2 ;
      RECT 105.985 0.000 106.055 0.210 ;
    END
  END rw0_rd_out[28]
  PIN rw0_rd_out[29]
    DIRECTION OUTPUT ;
    USE SIGNAL ;
    SHAPE ABUTMENT ;
    PORT
      LAYER metal2 ;
      RECT 107.125 0.000 107.195 0.210 ;
    END
  END rw0_rd_out[29]
  PIN rw0_rd_out[30]
    DIRECTION OUTPUT ;
    USE SIGNAL ;
    SHAPE ABUTMENT ;
    PORT
      LAYER metal2 ;
      RECT 108.265 0.000 108.335 0.210 ;
    END
  END rw0_rd_out[30]
  PIN rw0_rd_out[31]
    DIRECTION OUTPUT ;
    USE SIGNAL ;
    SHAPE ABUTMENT ;
    PORT
      LAYER metal2 ;
      RECT 109.405 0.000 109.475 0.210 ;
    END
  END rw0_rd_out[31]
  PIN rw0_rd_out[32]
    DIRECTION OUTPUT ;
    USE SIGNAL ;
    SHAPE ABUTMENT ;
    PORT
      LAYER metal2 ;
      RECT 1.105 253.190 1.175 253.400 ;
    END
  END rw0_rd_out[32]
  PIN rw0_rd_out[33]
    DIRECTION OUTPUT ;
    USE SIGNAL ;
    SHAPE ABUTMENT ;
    PORT
      LAYER metal2 ;
      RECT 3.195 253.190 3.265 253.400 ;
    END
  END rw0_rd_out[33]
  PIN rw0_rd_out[34]
    DIRECTION OUTPUT ;
    USE SIGNAL ;
    SHAPE ABUTMENT ;
    PORT
      LAYER metal2 ;
      RECT 5.285 253.190 5.355 253.400 ;
    END
  END rw0_rd_out[34]
  PIN rw0_rd_out[35]
    DIRECTION OUTPUT ;
    USE SIGNAL ;
    SHAPE ABUTMENT ;
    PORT
      LAYER metal2 ;
      RECT 7.375 253.190 7.445 253.400 ;
    END
  END rw0_rd_out[35]
  PIN rw0_rd_out[36]
    DIRECTION OUTPUT ;
    USE SIGNAL ;
    SHAPE ABUTMENT ;
    PORT
      LAYER metal2 ;
      RECT 9.465 253.190 9.535 253.400 ;
    END
  END rw0_rd_out[36]
  PIN rw0_rd_out[37]
    DIRECTION OUTPUT ;
    USE SIGNAL ;
    SHAPE ABUTMENT ;
    PORT
      LAYER metal2 ;
      RECT 11.555 253.190 11.625 253.400 ;
    END
  END rw0_rd_out[37]
  PIN rw0_rd_out[38]
    DIRECTION OUTPUT ;
    USE SIGNAL ;
    SHAPE ABUTMENT ;
    PORT
      LAYER metal2 ;
      RECT 13.645 253.190 13.715 253.400 ;
    END
  END rw0_rd_out[38]
  PIN rw0_rd_out[39]
    DIRECTION OUTPUT ;
    USE SIGNAL ;
    SHAPE ABUTMENT ;
    PORT
      LAYER metal2 ;
      RECT 15.735 253.190 15.805 253.400 ;
    END
  END rw0_rd_out[39]
  PIN rw0_rd_out[40]
    DIRECTION OUTPUT ;
    USE SIGNAL ;
    SHAPE ABUTMENT ;
    PORT
      LAYER metal2 ;
      RECT 17.825 253.190 17.895 253.400 ;
    END
  END rw0_rd_out[40]
  PIN rw0_rd_out[41]
    DIRECTION OUTPUT ;
    USE SIGNAL ;
    SHAPE ABUTMENT ;
    PORT
      LAYER metal2 ;
      RECT 19.915 253.190 19.985 253.400 ;
    END
  END rw0_rd_out[41]
  PIN rw0_rd_out[42]
    DIRECTION OUTPUT ;
    USE SIGNAL ;
    SHAPE ABUTMENT ;
    PORT
      LAYER metal2 ;
      RECT 22.005 253.190 22.075 253.400 ;
    END
  END rw0_rd_out[42]
  PIN rw0_rd_out[43]
    DIRECTION OUTPUT ;
    USE SIGNAL ;
    SHAPE ABUTMENT ;
    PORT
      LAYER metal2 ;
      RECT 24.095 253.190 24.165 253.400 ;
    END
  END rw0_rd_out[43]
  PIN rw0_rd_out[44]
    DIRECTION OUTPUT ;
    USE SIGNAL ;
    SHAPE ABUTMENT ;
    PORT
      LAYER metal2 ;
      RECT 26.185 253.190 26.255 253.400 ;
    END
  END rw0_rd_out[44]
  PIN rw0_rd_out[45]
    DIRECTION OUTPUT ;
    USE SIGNAL ;
    SHAPE ABUTMENT ;
    PORT
      LAYER metal2 ;
      RECT 28.275 253.190 28.345 253.400 ;
    END
  END rw0_rd_out[45]
  PIN rw0_rd_out[46]
    DIRECTION OUTPUT ;
    USE SIGNAL ;
    SHAPE ABUTMENT ;
    PORT
      LAYER metal2 ;
      RECT 30.365 253.190 30.435 253.400 ;
    END
  END rw0_rd_out[46]
  PIN rw0_rd_out[47]
    DIRECTION OUTPUT ;
    USE SIGNAL ;
    SHAPE ABUTMENT ;
    PORT
      LAYER metal2 ;
      RECT 32.455 253.190 32.525 253.400 ;
    END
  END rw0_rd_out[47]
  PIN rw0_rd_out[48]
    DIRECTION OUTPUT ;
    USE SIGNAL ;
    SHAPE ABUTMENT ;
    PORT
      LAYER metal2 ;
      RECT 34.545 253.190 34.615 253.400 ;
    END
  END rw0_rd_out[48]
  PIN rw0_rd_out[49]
    DIRECTION OUTPUT ;
    USE SIGNAL ;
    SHAPE ABUTMENT ;
    PORT
      LAYER metal2 ;
      RECT 36.635 253.190 36.705 253.400 ;
    END
  END rw0_rd_out[49]
  PIN rw0_rd_out[50]
    DIRECTION OUTPUT ;
    USE SIGNAL ;
    SHAPE ABUTMENT ;
    PORT
      LAYER metal2 ;
      RECT 38.725 253.190 38.795 253.400 ;
    END
  END rw0_rd_out[50]
  PIN rw0_rd_out[51]
    DIRECTION OUTPUT ;
    USE SIGNAL ;
    SHAPE ABUTMENT ;
    PORT
      LAYER metal2 ;
      RECT 40.815 253.190 40.885 253.400 ;
    END
  END rw0_rd_out[51]
  PIN rw0_rd_out[52]
    DIRECTION OUTPUT ;
    USE SIGNAL ;
    SHAPE ABUTMENT ;
    PORT
      LAYER metal2 ;
      RECT 42.905 253.190 42.975 253.400 ;
    END
  END rw0_rd_out[52]
  PIN rw0_rd_out[53]
    DIRECTION OUTPUT ;
    USE SIGNAL ;
    SHAPE ABUTMENT ;
    PORT
      LAYER metal2 ;
      RECT 44.995 253.190 45.065 253.400 ;
    END
  END rw0_rd_out[53]
  PIN rw0_rd_out[54]
    DIRECTION OUTPUT ;
    USE SIGNAL ;
    SHAPE ABUTMENT ;
    PORT
      LAYER metal2 ;
      RECT 47.085 253.190 47.155 253.400 ;
    END
  END rw0_rd_out[54]
  PIN rw0_rd_out[55]
    DIRECTION OUTPUT ;
    USE SIGNAL ;
    SHAPE ABUTMENT ;
    PORT
      LAYER metal2 ;
      RECT 49.175 253.190 49.245 253.400 ;
    END
  END rw0_rd_out[55]
  PIN rw0_rd_out[56]
    DIRECTION OUTPUT ;
    USE SIGNAL ;
    SHAPE ABUTMENT ;
    PORT
      LAYER metal2 ;
      RECT 51.265 253.190 51.335 253.400 ;
    END
  END rw0_rd_out[56]
  PIN rw0_rd_out[57]
    DIRECTION OUTPUT ;
    USE SIGNAL ;
    SHAPE ABUTMENT ;
    PORT
      LAYER metal2 ;
      RECT 53.355 253.190 53.425 253.400 ;
    END
  END rw0_rd_out[57]
  PIN rw0_rd_out[58]
    DIRECTION OUTPUT ;
    USE SIGNAL ;
    SHAPE ABUTMENT ;
    PORT
      LAYER metal2 ;
      RECT 55.445 253.190 55.515 253.400 ;
    END
  END rw0_rd_out[58]
  PIN rw0_rd_out[59]
    DIRECTION OUTPUT ;
    USE SIGNAL ;
    SHAPE ABUTMENT ;
    PORT
      LAYER metal2 ;
      RECT 57.535 253.190 57.605 253.400 ;
    END
  END rw0_rd_out[59]
  PIN rw0_rd_out[60]
    DIRECTION OUTPUT ;
    USE SIGNAL ;
    SHAPE ABUTMENT ;
    PORT
      LAYER metal2 ;
      RECT 59.625 253.190 59.695 253.400 ;
    END
  END rw0_rd_out[60]
  PIN rw0_rd_out[61]
    DIRECTION OUTPUT ;
    USE SIGNAL ;
    SHAPE ABUTMENT ;
    PORT
      LAYER metal2 ;
      RECT 61.715 253.190 61.785 253.400 ;
    END
  END rw0_rd_out[61]
  PIN rw0_rd_out[62]
    DIRECTION OUTPUT ;
    USE SIGNAL ;
    SHAPE ABUTMENT ;
    PORT
      LAYER metal2 ;
      RECT 63.805 253.190 63.875 253.400 ;
    END
  END rw0_rd_out[62]
  PIN rw0_rd_out[63]
    DIRECTION OUTPUT ;
    USE SIGNAL ;
    SHAPE ABUTMENT ;
    PORT
      LAYER metal2 ;
      RECT 65.895 253.190 65.965 253.400 ;
    END
  END rw0_rd_out[63]
  PIN rw1_rd_out[0]
    DIRECTION OUTPUT ;
    USE SIGNAL ;
    SHAPE ABUTMENT ;
    PORT
      LAYER metal2 ;
      RECT 110.545 0.000 110.615 0.210 ;
    END
  END rw1_rd_out[0]
  PIN rw1_rd_out[1]
    DIRECTION OUTPUT ;
    USE SIGNAL ;
    SHAPE ABUTMENT ;
    PORT
      LAYER metal2 ;
      RECT 111.685 0.000 111.755 0.210 ;
    END
  END rw1_rd_out[1]
  PIN rw1_rd_out[2]
    DIRECTION OUTPUT ;
    USE SIGNAL ;
    SHAPE ABUTMENT ;
    PORT
      LAYER metal2 ;
      RECT 112.825 0.000 112.895 0.210 ;
    END
  END rw1_rd_out[2]
  PIN rw1_rd_out[3]
    DIRECTION OUTPUT ;
    USE SIGNAL ;
    SHAPE ABUTMENT ;
    PORT
      LAYER metal2 ;
      RECT 113.965 0.000 114.035 0.210 ;
    END
  END rw1_rd_out[3]
  PIN rw1_rd_out[4]
    DIRECTION OUTPUT ;
    USE SIGNAL ;
    SHAPE ABUTMENT ;
    PORT
      LAYER metal2 ;
      RECT 115.105 0.000 115.175 0.210 ;
    END
  END rw1_rd_out[4]
  PIN rw1_rd_out[5]
    DIRECTION OUTPUT ;
    USE SIGNAL ;
    SHAPE ABUTMENT ;
    PORT
      LAYER metal2 ;
      RECT 116.245 0.000 116.315 0.210 ;
    END
  END rw1_rd_out[5]
  PIN rw1_rd_out[6]
    DIRECTION OUTPUT ;
    USE SIGNAL ;
    SHAPE ABUTMENT ;
    PORT
      LAYER metal2 ;
      RECT 117.385 0.000 117.455 0.210 ;
    END
  END rw1_rd_out[6]
  PIN rw1_rd_out[7]
    DIRECTION OUTPUT ;
    USE SIGNAL ;
    SHAPE ABUTMENT ;
    PORT
      LAYER metal2 ;
      RECT 118.525 0.000 118.595 0.210 ;
    END
  END rw1_rd_out[7]
  PIN rw1_rd_out[8]
    DIRECTION OUTPUT ;
    USE SIGNAL ;
    SHAPE ABUTMENT ;
    PORT
      LAYER metal2 ;
      RECT 119.665 0.000 119.735 0.210 ;
    END
  END rw1_rd_out[8]
  PIN rw1_rd_out[9]
    DIRECTION OUTPUT ;
    USE SIGNAL ;
    SHAPE ABUTMENT ;
    PORT
      LAYER metal2 ;
      RECT 120.805 0.000 120.875 0.210 ;
    END
  END rw1_rd_out[9]
  PIN rw1_rd_out[10]
    DIRECTION OUTPUT ;
    USE SIGNAL ;
    SHAPE ABUTMENT ;
    PORT
      LAYER metal2 ;
      RECT 121.945 0.000 122.015 0.210 ;
    END
  END rw1_rd_out[10]
  PIN rw1_rd_out[11]
    DIRECTION OUTPUT ;
    USE SIGNAL ;
    SHAPE ABUTMENT ;
    PORT
      LAYER metal2 ;
      RECT 123.085 0.000 123.155 0.210 ;
    END
  END rw1_rd_out[11]
  PIN rw1_rd_out[12]
    DIRECTION OUTPUT ;
    USE SIGNAL ;
    SHAPE ABUTMENT ;
    PORT
      LAYER metal2 ;
      RECT 124.225 0.000 124.295 0.210 ;
    END
  END rw1_rd_out[12]
  PIN rw1_rd_out[13]
    DIRECTION OUTPUT ;
    USE SIGNAL ;
    SHAPE ABUTMENT ;
    PORT
      LAYER metal2 ;
      RECT 125.365 0.000 125.435 0.210 ;
    END
  END rw1_rd_out[13]
  PIN rw1_rd_out[14]
    DIRECTION OUTPUT ;
    USE SIGNAL ;
    SHAPE ABUTMENT ;
    PORT
      LAYER metal2 ;
      RECT 126.505 0.000 126.575 0.210 ;
    END
  END rw1_rd_out[14]
  PIN rw1_rd_out[15]
    DIRECTION OUTPUT ;
    USE SIGNAL ;
    SHAPE ABUTMENT ;
    PORT
      LAYER metal2 ;
      RECT 127.645 0.000 127.715 0.210 ;
    END
  END rw1_rd_out[15]
  PIN rw1_rd_out[16]
    DIRECTION OUTPUT ;
    USE SIGNAL ;
    SHAPE ABUTMENT ;
    PORT
      LAYER metal2 ;
      RECT 128.785 0.000 128.855 0.210 ;
    END
  END rw1_rd_out[16]
  PIN rw1_rd_out[17]
    DIRECTION OUTPUT ;
    USE SIGNAL ;
    SHAPE ABUTMENT ;
    PORT
      LAYER metal2 ;
      RECT 129.925 0.000 129.995 0.210 ;
    END
  END rw1_rd_out[17]
  PIN rw1_rd_out[18]
    DIRECTION OUTPUT ;
    USE SIGNAL ;
    SHAPE ABUTMENT ;
    PORT
      LAYER metal2 ;
      RECT 131.065 0.000 131.135 0.210 ;
    END
  END rw1_rd_out[18]
  PIN rw1_rd_out[19]
    DIRECTION OUTPUT ;
    USE SIGNAL ;
    SHAPE ABUTMENT ;
    PORT
      LAYER metal2 ;
      RECT 132.205 0.000 132.275 0.210 ;
    END
  END rw1_rd_out[19]
  PIN rw1_rd_out[20]
    DIRECTION OUTPUT ;
    USE SIGNAL ;
    SHAPE ABUTMENT ;
    PORT
      LAYER metal2 ;
      RECT 133.345 0.000 133.415 0.210 ;
    END
  END rw1_rd_out[20]
  PIN rw1_rd_out[21]
    DIRECTION OUTPUT ;
    USE SIGNAL ;
    SHAPE ABUTMENT ;
    PORT
      LAYER metal2 ;
      RECT 134.485 0.000 134.555 0.210 ;
    END
  END rw1_rd_out[21]
  PIN rw1_rd_out[22]
    DIRECTION OUTPUT ;
    USE SIGNAL ;
    SHAPE ABUTMENT ;
    PORT
      LAYER metal2 ;
      RECT 135.625 0.000 135.695 0.210 ;
    END
  END rw1_rd_out[22]
  PIN rw1_rd_out[23]
    DIRECTION OUTPUT ;
    USE SIGNAL ;
    SHAPE ABUTMENT ;
    PORT
      LAYER metal2 ;
      RECT 136.765 0.000 136.835 0.210 ;
    END
  END rw1_rd_out[23]
  PIN rw1_rd_out[24]
    DIRECTION OUTPUT ;
    USE SIGNAL ;
    SHAPE ABUTMENT ;
    PORT
      LAYER metal2 ;
      RECT 137.905 0.000 137.975 0.210 ;
    END
  END rw1_rd_out[24]
  PIN rw1_rd_out[25]
    DIRECTION OUTPUT ;
    USE SIGNAL ;
    SHAPE ABUTMENT ;
    PORT
      LAYER metal2 ;
      RECT 139.045 0.000 139.115 0.210 ;
    END
  END rw1_rd_out[25]
  PIN rw1_rd_out[26]
    DIRECTION OUTPUT ;
    USE SIGNAL ;
    SHAPE ABUTMENT ;
    PORT
      LAYER metal2 ;
      RECT 140.185 0.000 140.255 0.210 ;
    END
  END rw1_rd_out[26]
  PIN rw1_rd_out[27]
    DIRECTION OUTPUT ;
    USE SIGNAL ;
    SHAPE ABUTMENT ;
    PORT
      LAYER metal2 ;
      RECT 141.325 0.000 141.395 0.210 ;
    END
  END rw1_rd_out[27]
  PIN rw1_rd_out[28]
    DIRECTION OUTPUT ;
    USE SIGNAL ;
    SHAPE ABUTMENT ;
    PORT
      LAYER metal2 ;
      RECT 142.465 0.000 142.535 0.210 ;
    END
  END rw1_rd_out[28]
  PIN rw1_rd_out[29]
    DIRECTION OUTPUT ;
    USE SIGNAL ;
    SHAPE ABUTMENT ;
    PORT
      LAYER metal2 ;
      RECT 143.605 0.000 143.675 0.210 ;
    END
  END rw1_rd_out[29]
  PIN rw1_rd_out[30]
    DIRECTION OUTPUT ;
    USE SIGNAL ;
    SHAPE ABUTMENT ;
    PORT
      LAYER metal2 ;
      RECT 144.745 0.000 144.815 0.210 ;
    END
  END rw1_rd_out[30]
  PIN rw1_rd_out[31]
    DIRECTION OUTPUT ;
    USE SIGNAL ;
    SHAPE ABUTMENT ;
    PORT
      LAYER metal2 ;
      RECT 145.885 0.000 145.955 0.210 ;
    END
  END rw1_rd_out[31]
  PIN rw1_rd_out[32]
    DIRECTION OUTPUT ;
    USE SIGNAL ;
    SHAPE ABUTMENT ;
    PORT
      LAYER metal2 ;
      RECT 67.985 253.190 68.055 253.400 ;
    END
  END rw1_rd_out[32]
  PIN rw1_rd_out[33]
    DIRECTION OUTPUT ;
    USE SIGNAL ;
    SHAPE ABUTMENT ;
    PORT
      LAYER metal2 ;
      RECT 70.075 253.190 70.145 253.400 ;
    END
  END rw1_rd_out[33]
  PIN rw1_rd_out[34]
    DIRECTION OUTPUT ;
    USE SIGNAL ;
    SHAPE ABUTMENT ;
    PORT
      LAYER metal2 ;
      RECT 72.165 253.190 72.235 253.400 ;
    END
  END rw1_rd_out[34]
  PIN rw1_rd_out[35]
    DIRECTION OUTPUT ;
    USE SIGNAL ;
    SHAPE ABUTMENT ;
    PORT
      LAYER metal2 ;
      RECT 74.255 253.190 74.325 253.400 ;
    END
  END rw1_rd_out[35]
  PIN rw1_rd_out[36]
    DIRECTION OUTPUT ;
    USE SIGNAL ;
    SHAPE ABUTMENT ;
    PORT
      LAYER metal2 ;
      RECT 76.345 253.190 76.415 253.400 ;
    END
  END rw1_rd_out[36]
  PIN rw1_rd_out[37]
    DIRECTION OUTPUT ;
    USE SIGNAL ;
    SHAPE ABUTMENT ;
    PORT
      LAYER metal2 ;
      RECT 78.435 253.190 78.505 253.400 ;
    END
  END rw1_rd_out[37]
  PIN rw1_rd_out[38]
    DIRECTION OUTPUT ;
    USE SIGNAL ;
    SHAPE ABUTMENT ;
    PORT
      LAYER metal2 ;
      RECT 80.525 253.190 80.595 253.400 ;
    END
  END rw1_rd_out[38]
  PIN rw1_rd_out[39]
    DIRECTION OUTPUT ;
    USE SIGNAL ;
    SHAPE ABUTMENT ;
    PORT
      LAYER metal2 ;
      RECT 82.615 253.190 82.685 253.400 ;
    END
  END rw1_rd_out[39]
  PIN rw1_rd_out[40]
    DIRECTION OUTPUT ;
    USE SIGNAL ;
    SHAPE ABUTMENT ;
    PORT
      LAYER metal2 ;
      RECT 84.705 253.190 84.775 253.400 ;
    END
  END rw1_rd_out[40]
  PIN rw1_rd_out[41]
    DIRECTION OUTPUT ;
    USE SIGNAL ;
    SHAPE ABUTMENT ;
    PORT
      LAYER metal2 ;
      RECT 86.795 253.190 86.865 253.400 ;
    END
  END rw1_rd_out[41]
  PIN rw1_rd_out[42]
    DIRECTION OUTPUT ;
    USE SIGNAL ;
    SHAPE ABUTMENT ;
    PORT
      LAYER metal2 ;
      RECT 88.885 253.190 88.955 253.400 ;
    END
  END rw1_rd_out[42]
  PIN rw1_rd_out[43]
    DIRECTION OUTPUT ;
    USE SIGNAL ;
    SHAPE ABUTMENT ;
    PORT
      LAYER metal2 ;
      RECT 90.975 253.190 91.045 253.400 ;
    END
  END rw1_rd_out[43]
  PIN rw1_rd_out[44]
    DIRECTION OUTPUT ;
    USE SIGNAL ;
    SHAPE ABUTMENT ;
    PORT
      LAYER metal2 ;
      RECT 93.065 253.190 93.135 253.400 ;
    END
  END rw1_rd_out[44]
  PIN rw1_rd_out[45]
    DIRECTION OUTPUT ;
    USE SIGNAL ;
    SHAPE ABUTMENT ;
    PORT
      LAYER metal2 ;
      RECT 95.155 253.190 95.225 253.400 ;
    END
  END rw1_rd_out[45]
  PIN rw1_rd_out[46]
    DIRECTION OUTPUT ;
    USE SIGNAL ;
    SHAPE ABUTMENT ;
    PORT
      LAYER metal2 ;
      RECT 97.245 253.190 97.315 253.400 ;
    END
  END rw1_rd_out[46]
  PIN rw1_rd_out[47]
    DIRECTION OUTPUT ;
    USE SIGNAL ;
    SHAPE ABUTMENT ;
    PORT
      LAYER metal2 ;
      RECT 99.335 253.190 99.405 253.400 ;
    END
  END rw1_rd_out[47]
  PIN rw1_rd_out[48]
    DIRECTION OUTPUT ;
    USE SIGNAL ;
    SHAPE ABUTMENT ;
    PORT
      LAYER metal2 ;
      RECT 101.425 253.190 101.495 253.400 ;
    END
  END rw1_rd_out[48]
  PIN rw1_rd_out[49]
    DIRECTION OUTPUT ;
    USE SIGNAL ;
    SHAPE ABUTMENT ;
    PORT
      LAYER metal2 ;
      RECT 103.515 253.190 103.585 253.400 ;
    END
  END rw1_rd_out[49]
  PIN rw1_rd_out[50]
    DIRECTION OUTPUT ;
    USE SIGNAL ;
    SHAPE ABUTMENT ;
    PORT
      LAYER metal2 ;
      RECT 105.605 253.190 105.675 253.400 ;
    END
  END rw1_rd_out[50]
  PIN rw1_rd_out[51]
    DIRECTION OUTPUT ;
    USE SIGNAL ;
    SHAPE ABUTMENT ;
    PORT
      LAYER metal2 ;
      RECT 107.695 253.190 107.765 253.400 ;
    END
  END rw1_rd_out[51]
  PIN rw1_rd_out[52]
    DIRECTION OUTPUT ;
    USE SIGNAL ;
    SHAPE ABUTMENT ;
    PORT
      LAYER metal2 ;
      RECT 109.785 253.190 109.855 253.400 ;
    END
  END rw1_rd_out[52]
  PIN rw1_rd_out[53]
    DIRECTION OUTPUT ;
    USE SIGNAL ;
    SHAPE ABUTMENT ;
    PORT
      LAYER metal2 ;
      RECT 111.875 253.190 111.945 253.400 ;
    END
  END rw1_rd_out[53]
  PIN rw1_rd_out[54]
    DIRECTION OUTPUT ;
    USE SIGNAL ;
    SHAPE ABUTMENT ;
    PORT
      LAYER metal2 ;
      RECT 113.965 253.190 114.035 253.400 ;
    END
  END rw1_rd_out[54]
  PIN rw1_rd_out[55]
    DIRECTION OUTPUT ;
    USE SIGNAL ;
    SHAPE ABUTMENT ;
    PORT
      LAYER metal2 ;
      RECT 116.055 253.190 116.125 253.400 ;
    END
  END rw1_rd_out[55]
  PIN rw1_rd_out[56]
    DIRECTION OUTPUT ;
    USE SIGNAL ;
    SHAPE ABUTMENT ;
    PORT
      LAYER metal2 ;
      RECT 118.145 253.190 118.215 253.400 ;
    END
  END rw1_rd_out[56]
  PIN rw1_rd_out[57]
    DIRECTION OUTPUT ;
    USE SIGNAL ;
    SHAPE ABUTMENT ;
    PORT
      LAYER metal2 ;
      RECT 120.235 253.190 120.305 253.400 ;
    END
  END rw1_rd_out[57]
  PIN rw1_rd_out[58]
    DIRECTION OUTPUT ;
    USE SIGNAL ;
    SHAPE ABUTMENT ;
    PORT
      LAYER metal2 ;
      RECT 122.325 253.190 122.395 253.400 ;
    END
  END rw1_rd_out[58]
  PIN rw1_rd_out[59]
    DIRECTION OUTPUT ;
    USE SIGNAL ;
    SHAPE ABUTMENT ;
    PORT
      LAYER metal2 ;
      RECT 124.415 253.190 124.485 253.400 ;
    END
  END rw1_rd_out[59]
  PIN rw1_rd_out[60]
    DIRECTION OUTPUT ;
    USE SIGNAL ;
    SHAPE ABUTMENT ;
    PORT
      LAYER metal2 ;
      RECT 126.505 253.190 126.575 253.400 ;
    END
  END rw1_rd_out[60]
  PIN rw1_rd_out[61]
    DIRECTION OUTPUT ;
    USE SIGNAL ;
    SHAPE ABUTMENT ;
    PORT
      LAYER metal2 ;
      RECT 128.595 253.190 128.665 253.400 ;
    END
  END rw1_rd_out[61]
  PIN rw1_rd_out[62]
    DIRECTION OUTPUT ;
    USE SIGNAL ;
    SHAPE ABUTMENT ;
    PORT
      LAYER metal2 ;
      RECT 130.685 253.190 130.755 253.400 ;
    END
  END rw1_rd_out[62]
  PIN rw1_rd_out[63]
    DIRECTION OUTPUT ;
    USE SIGNAL ;
    SHAPE ABUTMENT ;
    PORT
      LAYER metal2 ;
      RECT 132.775 253.190 132.845 253.400 ;
    END
  END rw1_rd_out[63]
  PIN rw0_addr_in[0]
    DIRECTION INPUT ;
    USE SIGNAL ;
    SHAPE ABUTMENT ;
    PORT
      LAYER metal3 ;
      RECT 0.000 197.925 0.210 197.995 ;
    END
  END rw0_addr_in[0]
  PIN rw0_addr_in[1]
    DIRECTION INPUT ;
    USE SIGNAL ;
    SHAPE ABUTMENT ;
    PORT
      LAYER metal3 ;
      RECT 0.000 204.085 0.210 204.155 ;
    END
  END rw0_addr_in[1]
  PIN rw0_addr_in[2]
    DIRECTION INPUT ;
    USE SIGNAL ;
    SHAPE ABUTMENT ;
    PORT
      LAYER metal3 ;
      RECT 0.000 210.245 0.210 210.315 ;
    END
  END rw0_addr_in[2]
  PIN rw0_addr_in[3]
    DIRECTION INPUT ;
    USE SIGNAL ;
    SHAPE ABUTMENT ;
    PORT
      LAYER metal3 ;
      RECT 0.000 216.405 0.210 216.475 ;
    END
  END rw0_addr_in[3]
  PIN rw0_addr_in[4]
    DIRECTION INPUT ;
    USE SIGNAL ;
    SHAPE ABUTMENT ;
    PORT
      LAYER metal3 ;
      RECT 154.640 197.925 154.850 197.995 ;
    END
  END rw0_addr_in[4]
  PIN rw0_addr_in[5]
    DIRECTION INPUT ;
    USE SIGNAL ;
    SHAPE ABUTMENT ;
    PORT
      LAYER metal3 ;
      RECT 154.640 204.085 154.850 204.155 ;
    END
  END rw0_addr_in[5]
  PIN rw0_addr_in[6]
    DIRECTION INPUT ;
    USE SIGNAL ;
    SHAPE ABUTMENT ;
    PORT
      LAYER metal3 ;
      RECT 154.640 210.245 154.850 210.315 ;
    END
  END rw0_addr_in[6]
  PIN rw0_addr_in[7]
    DIRECTION INPUT ;
    USE SIGNAL ;
    SHAPE ABUTMENT ;
    PORT
      LAYER metal3 ;
      RECT 154.640 216.405 154.850 216.475 ;
    END
  END rw0_addr_in[7]
  PIN rw1_addr_in[0]
    DIRECTION INPUT ;
    USE SIGNAL ;
    SHAPE ABUTMENT ;
    PORT
      LAYER metal3 ;
      RECT 0.000 222.565 0.210 222.635 ;
    END
  END rw1_addr_in[0]
  PIN rw1_addr_in[1]
    DIRECTION INPUT ;
    USE SIGNAL ;
    SHAPE ABUTMENT ;
    PORT
      LAYER metal3 ;
      RECT 0.000 228.725 0.210 228.795 ;
    END
  END rw1_addr_in[1]
  PIN rw1_addr_in[2]
    DIRECTION INPUT ;
    USE SIGNAL ;
    SHAPE ABUTMENT ;
    PORT
      LAYER metal3 ;
      RECT 0.000 234.885 0.210 234.955 ;
    END
  END rw1_addr_in[2]
  PIN rw1_addr_in[3]
    DIRECTION INPUT ;
    USE SIGNAL ;
    SHAPE ABUTMENT ;
    PORT
      LAYER metal3 ;
      RECT 0.000 241.045 0.210 241.115 ;
    END
  END rw1_addr_in[3]
  PIN rw1_addr_in[4]
    DIRECTION INPUT ;
    USE SIGNAL ;
    SHAPE ABUTMENT ;
    PORT
      LAYER metal3 ;
      RECT 154.640 222.565 154.850 222.635 ;
    END
  END rw1_addr_in[4]
  PIN rw1_addr_in[5]
    DIRECTION INPUT ;
    USE SIGNAL ;
    SHAPE ABUTMENT ;
    PORT
      LAYER metal3 ;
      RECT 154.640 228.725 154.850 228.795 ;
    END
  END rw1_addr_in[5]
  PIN rw1_addr_in[6]
    DIRECTION INPUT ;
    USE SIGNAL ;
    SHAPE ABUTMENT ;
    PORT
      LAYER metal3 ;
      RECT 154.640 234.885 154.850 234.955 ;
    END
  END rw1_addr_in[6]
  PIN rw1_addr_in[7]
    DIRECTION INPUT ;
    USE SIGNAL ;
    SHAPE ABUTMENT ;
    PORT
      LAYER metal3 ;
      RECT 154.640 241.045 154.850 241.115 ;
    END
  END rw1_addr_in[7]
  PIN rw0_we_in
    DIRECTION INPUT ;
    USE SIGNAL ;
    SHAPE ABUTMENT ;
    PORT
      LAYER metal2 ;
      RECT 134.865 253.190 134.935 253.400 ;
    END
  END rw0_we_in
  PIN rw0_ce_in
    DIRECTION INPUT ;
    USE SIGNAL ;
    SHAPE ABUTMENT ;
    PORT
      LAYER metal2 ;
      RECT 136.955 253.190 137.025 253.400 ;
    END
  END rw0_ce_in
  PIN rw0_clk
    DIRECTION INPUT ;
    USE SIGNAL ;
    SHAPE ABUTMENT ;
    PORT
      LAYER metal2 ;
      RECT 139.045 253.190 139.115 253.400 ;
    END
  END rw0_clk
  PIN rw1_we_in
    DIRECTION INPUT ;
    USE SIGNAL ;
    SHAPE ABUTMENT ;
    PORT
      LAYER metal2 ;
      RECT 141.135 253.190 141.205 253.400 ;
    END
  END rw1_we_in
  PIN rw1_ce_in
    DIRECTION INPUT ;
    USE SIGNAL ;
    SHAPE ABUTMENT ;
    PORT
      LAYER metal2 ;
      RECT 143.225 253.190 143.295 253.400 ;
    END
  END rw1_ce_in
  PIN rw1_clk
    DIRECTION INPUT ;
    USE SIGNAL ;
    SHAPE ABUTMENT ;
    PORT
      LAYER metal2 ;
      RECT 145.315 253.190 145.385 253.400 ;
    END
  END rw1_clk
  PIN VSS
    DIRECTION INOUT ;
    USE GROUND ;
    PORT
      LAYER metal4 ;
      RECT 1.000 0.840 1.280 252.560 ;
      RECT 3.240 0.840 3.520 252.560 ;
      RECT 5.480 0.840 5.760 252.560 ;
      RECT 7.720 0.840 8.000 252.560 ;
      RECT 9.960 0.840 10.240 252.560 ;
      RECT 12.200 0.840 12.480 252.560 ;
      RECT 14.440 0.840 14.720 252.560 ;
      RECT 16.680 0.840 16.960 252.560 ;
      RECT 18.920 0.840 19.200 252.560 ;
      RECT 21.160 0.840 21.440 252.560 ;
      RECT 23.400 0.840 23.680 252.560 ;
      RECT 25.640 0.840 25.920 252.560 ;
      RECT 27.880 0.840 28.160 252.560 ;
      RECT 30.120 0.840 30.400 252.560 ;
      RECT 32.360 0.840 32.640 252.560 ;
      RECT 34.600 0.840 34.880 252.560 ;
      RECT 36.840 0.840 37.120 252.560 ;
      RECT 39.080 0.840 39.360 252.560 ;
      RECT 41.320 0.840 41.600 252.560 ;
      RECT 43.560 0.840 43.840 252.560 ;
      RECT 45.800 0.840 46.080 252.560 ;
      RECT 48.040 0.840 48.320 252.560 ;
      RECT 50.280 0.840 50.560 252.560 ;
      RECT 52.520 0.840 52.800 252.560 ;
      RECT 54.760 0.840 55.040 252.560 ;
      RECT 57.000 0.840 57.280 252.560 ;
      RECT 59.240 0.840 59.520 252.560 ;
      RECT 61.480 0.840 61.760 252.560 ;
      RECT 63.720 0.840 64.000 252.560 ;
      RECT 65.960 0.840 66.240 252.560 ;
      RECT 68.200 0.840 68.480 252.560 ;
      RECT 70.440 0.840 70.720 252.560 ;
      RECT 72.680 0.840 72.960 252.560 ;
      RECT 74.920 0.840 75.200 252.560 ;
      RECT 77.160 0.840 77.440 252.560 ;
      RECT 79.400 0.840 79.680 252.560 ;
      RECT 81.640 0.840 81.920 252.560 ;
      RECT 83.880 0.840 84.160 252.560 ;
      RECT 86.120 0.840 86.400 252.560 ;
      RECT 88.360 0.840 88.640 252.560 ;
      RECT 90.600 0.840 90.880 252.560 ;
      RECT 92.840 0.840 93.120 252.560 ;
      RECT 95.080 0.840 95.360 252.560 ;
      RECT 97.320 0.840 97.600 252.560 ;
      RECT 99.560 0.840 99.840 252.560 ;
      RECT 101.800 0.840 102.080 252.560 ;
      RECT 104.040 0.840 104.320 252.560 ;
      RECT 106.280 0.840 106.560 252.560 ;
      RECT 108.520 0.840 108.800 252.560 ;
      RECT 110.760 0.840 111.040 252.560 ;
      RECT 113.000 0.840 113.280 252.560 ;
      RECT 115.240 0.840 115.520 252.560 ;
      RECT 117.480 0.840 117.760 252.560 ;
      RECT 119.720 0.840 120.000 252.560 ;
      RECT 121.960 0.840 122.240 252.560 ;
      RECT 124.200 0.840 124.480 252.560 ;
      RECT 126.440 0.840 126.720 252.560 ;
      RECT 128.680 0.840 128.960 252.560 ;
      RECT 130.920 0.840 131.200 252.560 ;
      RECT 133.160 0.840 133.440 252.560 ;
      RECT 135.400 0.840 135.680 252.560 ;
      RECT 137.640 0.840 137.920 252.560 ;
      RECT 139.880 0.840 140.160 252.560 ;
      RECT 142.120 0.840 142.400 252.560 ;
      RECT 144.360 0.840 144.640 252.560 ;
      RECT 146.600 0.840 146.880 252.560 ;
      RECT 148.840 0.840 149.120 252.560 ;
      RECT 151.080 0.840 151.360 252.560 ;
      RECT 153.320 0.840 153.600 252.560 ;
    END
  END VSS
  PIN VDD
    DIRECTION INOUT ;
    USE POWER ;
    PORT
      LAYER metal4 ;
      RECT 2.120 0.840 2.400 252.560 ;
      RECT 4.360 0.840 4.640 252.560 ;
      RECT 6.600 0.840 6.880 252.560 ;
      RECT 8.840 0.840 9.120 252.560 ;
      RECT 11.080 0.840 11.360 252.560 ;
      RECT 13.320 0.840 13.600 252.560 ;
      RECT 15.560 0.840 15.840 252.560 ;
      RECT 17.800 0.840 18.080 252.560 ;
      RECT 20.040 0.840 20.320 252.560 ;
      RECT 22.280 0.840 22.560 252.560 ;
      RECT 24.520 0.840 24.800 252.560 ;
      RECT 26.760 0.840 27.040 252.560 ;
      RECT 29.000 0.840 29.280 252.560 ;
      RECT 31.240 0.840 31.520 252.560 ;
      RECT 33.480 0.840 33.760 252.560 ;
      RECT 35.720 0.840 36.000 252.560 ;
      RECT 37.960 0.840 38.240 252.560 ;
      RECT 40.200 0.840 40.480 252.560 ;
      RECT 42.440 0.840 42.720 252.560 ;
      RECT 44.680 0.840 44.960 252.560 ;
      RECT 46.920 0.840 47.200 252.560 ;
      RECT 49.160 0.840 49.440 252.560 ;
      RECT 51.400 0.840 51.680 252.560 ;
      RECT 53.640 0.840 53.920 252.560 ;
      RECT 55.880 0.840 56.160 252.560 ;
      RECT 58.120 0.840 58.400 252.560 ;
      RECT 60.360 0.840 60.640 252.560 ;
      RECT 62.600 0.840 62.880 252.560 ;
      RECT 64.840 0.840 65.120 252.560 ;
      RECT 67.080 0.840 67.360 252.560 ;
      RECT 69.320 0.840 69.600 252.560 ;
      RECT 71.560 0.840 71.840 252.560 ;
      RECT 73.800 0.840 74.080 252.560 ;
      RECT 76.040 0.840 76.320 252.560 ;
      RECT 78.280 0.840 78.560 252.560 ;
      RECT 80.520 0.840 80.800 252.560 ;
      RECT 82.760 0.840 83.040 252.560 ;
      RECT 85.000 0.840 85.280 252.560 ;
      RECT 87.240 0.840 87.520 252.560 ;
      RECT 89.480 0.840 89.760 252.560 ;
      RECT 91.720 0.840 92.000 252.560 ;
      RECT 93.960 0.840 94.240 252.560 ;
      RECT 96.200 0.840 96.480 252.560 ;
      RECT 98.440 0.840 98.720 252.560 ;
      RECT 100.680 0.840 100.960 252.560 ;
      RECT 102.920 0.840 103.200 252.560 ;
      RECT 105.160 0.840 105.440 252.560 ;
      RECT 107.400 0.840 107.680 252.560 ;
      RECT 109.640 0.840 109.920 252.560 ;
      RECT 111.880 0.840 112.160 252.560 ;
      RECT 114.120 0.840 114.400 252.560 ;
      RECT 116.360 0.840 116.640 252.560 ;
      RECT 118.600 0.840 118.880 252.560 ;
      RECT 120.840 0.840 121.120 252.560 ;
      RECT 123.080 0.840 123.360 252.560 ;
      RECT 125.320 0.840 125.600 252.560 ;
      RECT 127.560 0.840 127.840 252.560 ;
      RECT 129.800 0.840 130.080 252.560 ;
      RECT 132.040 0.840 132.320 252.560 ;
      RECT 134.280 0.840 134.560 252.560 ;
      RECT 136.520 0.840 136.800 252.560 ;
      RECT 138.760 0.840 139.040 252.560 ;
      RECT 141.000 0.840 141.280 252.560 ;
      RECT 143.240 0.840 143.520 252.560 ;
      RECT 145.480 0.840 145.760 252.560 ;
      RECT 147.720 0.840 148.000 252.560 ;
      RECT 149.960 0.840 150.240 252.560 ;
      RECT 152.200 0.840 152.480 252.560 ;
      RECT 154.440 0.840 154.720 252.560 ;
    END
  END VDD
  OBS
    LAYER metal1 ;
    RECT 0 0 154.850 253.400 ;
    LAYER metal2 ;
    RECT 0 0 154.850 253.400 ;
    LAYER metal3 ;
    RECT 0 0 154.850 253.400 ;
    LAYER metal4 ;
    RECT 0 0 154.850 253.400 ;
    LAYER OVERLAP ;
    RECT 0 0 154.850 253.400 ;
  END
END fakeram_w64_l256

END LIBRARY
